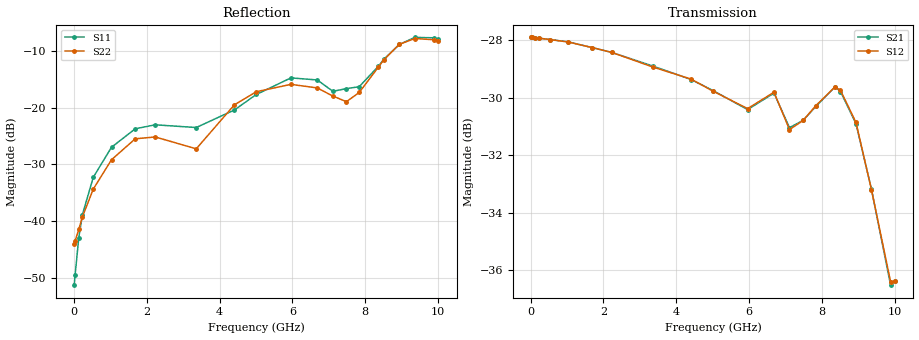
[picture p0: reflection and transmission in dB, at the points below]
! Device ID: PE43704
! Dir: z:\PE43704\PE43704_Char_1_20130516\PE43704\AMB\3p400V\27p00dB
! Serial: 14
! Insertion: A
! Impedance: 50 ohm
! Temp: Amb
! VDD: 3.400V
! Attenuation Step: 27.00dB
! IDD: 1.140195e-01mA
#  Hz  S  RI  R  50
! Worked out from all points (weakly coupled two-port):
!   401 points, 10 MHz to 10.01 GHz, reference 50 ohm
!   highest |S21| = -27.88 dB at 35 MHz (marker M1); lowest = -36.5 dB at 9.885 GHz (marker M2)
!   lowest |S11| = -51.2 dB at 10 MHz (marker M3), VSWR 1.01, Z = 50.3 + j0.0412 ohm
!   |S11| at or under -10 dB: start of sweep to 8.723 GHz
!   |S22| runs from -44.1 to -7.8 dB; largest |S21 - S12| = 0.00064
!   S11 on the Smith chart (normalised r, x): 10 MHz: 1.01, +0.00; 7.485 GHz: 0.79, +0.16; 8.51 GHz: 0.81, +0.46; 9.36 GHz: 0.54, +0.49; 10.01 GHz: 0.47, +0.28
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1e7  0.00271 0.000409  0.0403 -0.000149  0.0403 -0.000141  0.00625 0.000379
3.5e7  0.00286 0.00177  0.0403 -0.000373  0.0403 -0.000394  0.00654 0.00146
1.35e8  0.00255 0.00667  0.0402 -0.00142  0.0402 -0.00145  0.00626 0.0057
2.35e8  0.000861 0.0114  0.0401 -0.00247  0.0401 -0.0024  0.00481 0.00982
5.35e8  -0.00767 0.0232  0.0396 -0.0053  0.0396 -0.0053  -0.00354 0.0189
1.035e9  -0.0332 0.0301  0.0383 -0.00999  0.0383 -0.00991  -0.0276 0.0212
1.685e9  -0.0631 0.016  0.0355 -0.0154  0.0355 -0.0154  -0.0531 0.00238
2.235e9  -0.0706 -0.000686  0.0326 -0.0194  0.0326 -0.0194  -0.0538 -0.0123
3.36e9  -0.0668 0.000579  0.0253 -0.0255  0.0252 -0.0254  -0.0431 0.00511
4.41e9  -0.0841 0.045  0.0186 -0.0285  0.0187 -0.0285  -0.0925 0.0517
5.01e9  -0.1078 0.0737  0.0152 -0.0288  0.0152 -0.0287  -0.1257 0.0569
5.96e9  -0.1549 0.0969  0.00958 -0.0286  0.00968 -0.0287  -0.1508 0.0542
6.685e9  -0.1542 0.083  0.00679 -0.0315  0.00688 -0.0316  -0.1392 0.0532
7.11e9  -0.1235 0.0643  0.00169 -0.028  0.00156 -0.0278  -0.1063 0.0683
7.485e9  -0.1098 0.0976  0.00233 -0.0288  0.00218 -0.0288  -0.0755 0.0839
7.835e9  -0.0662 0.1378  0.00171 -0.0305  0.0018 -0.0306  -0.0592 0.1224
8.36e9  -0.0335 0.2286  -0.00655 -0.0324  -0.00644 -0.0324  -0.0734 0.2151
8.51e9  -0.0362 0.2639  -0.00916 -0.0311  -0.00909 -0.0313  -0.0857 0.2493
8.935e9  -0.0878 0.3487  -0.0139 -0.0249  -0.014 -0.025  -0.152 0.3268
9.36e9  -0.1786 0.3747  -0.0128 -0.0178  -0.013 -0.0176  -0.2376 0.3288
9.885e9  -0.2935 0.2886  -0.00514 -0.014  -0.00519 -0.0142  -0.3369 0.2073
1.001e10  -0.3132 0.2503  -0.00287 -0.0149  -0.00273 -0.0149  -0.3529 0.1634
